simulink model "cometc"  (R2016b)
settings: Solver=ode45  StartTime=0.0  StopTime=298.0  RelTol=1e-3  EnableMultiTasking=on
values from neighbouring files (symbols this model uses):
  d11 = 215*100    (= 21500)    [parameter.m]
  d22 = 147*10^3    (= 147000)    [parameter.m]
  d33 = 802*10^4    (= 8020000)    [parameter.m]
  delta1 = 0.00001    (= 1e-05)    [parameter.m]
  delta2 = 0.0001    [parameter.m]
  garma1 = 10000    [parameter.m]
  garma2 = 100    [parameter.m]
  kr = 0.05    [parameter.m]
  krou = 0.4    [parameter.m]
  ktheat = 0.8    [parameter.m]
  ku = 0.05    [parameter.m]
  lam0 = 0    [parameter.m]
  m11 = 120*10^3    (= 120000)    [parameter.m]
  m22 = 177.9*10^3    (= 177900)    [parameter.m]
  m33 = 636*10^5    (= 63600000)    [parameter.m]
  rou0 = 10    [parameter.m]
  T1 = 0.8    [parameter.m]
  T2 = 0.3    [parameter.m]
libraries: simulink x4

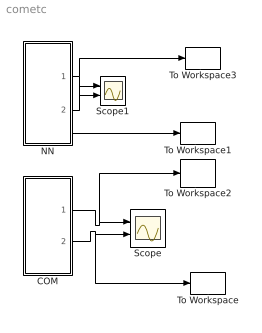
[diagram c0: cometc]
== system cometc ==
  COM : Subsystem
  NN : Subsystem
  Scope : Scope  NumInputPorts=2
  Scope1 : Scope  NumInputPorts=2
  To Workspace : ToWorkspace  VariableName=comtheat  SampleTime=-1
  To Workspace1 : ToWorkspace  VariableName=nntheat  SampleTime=-1
  To Workspace2 : ToWorkspace  VariableName=comrou  SampleTime=-1
  To Workspace3 : ToWorkspace  VariableName=nnrou  SampleTime=-1
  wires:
  NN/1(rous) -> To Workspace3/1, Scope1/1
  NN/2(theta) -> To Workspace1/1, Scope1/2
  COM/1(rous) -> To Workspace2/1, Scope/1
  COM/2(theta) -> To Workspace/1, Scope/2

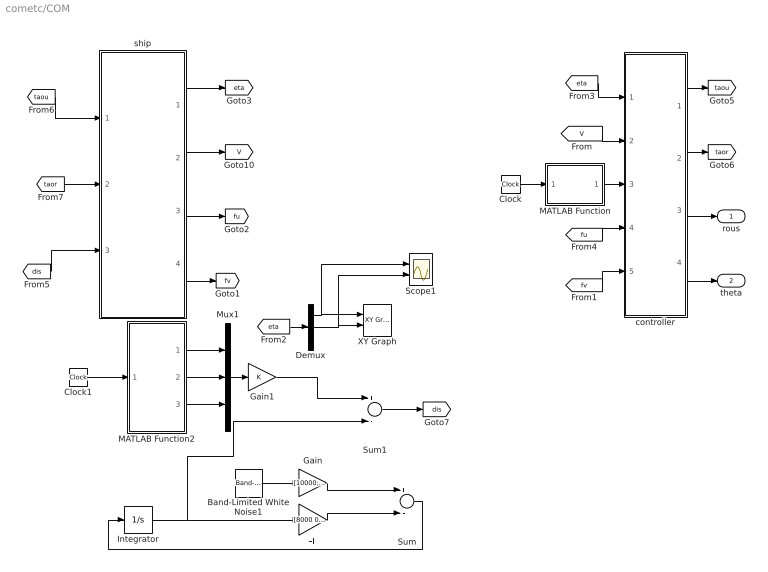
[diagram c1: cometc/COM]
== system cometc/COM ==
  -T : Gain  Gain=[8000 0 0;0 8000 0;0 0 80000]  Multiplication=Matrix(K*u)
  Band-Limited White Noise1 : simulink/Sources/Band-Limited White Noise  Cov=[0.1]  Ts=0.1  seed=[23341]
  Clock : Clock
  Clock1 : Clock
  Demux : Demux  Outputs=3
  Gain : Gain  Gain=[10000;10000;100000]
  Gain1 : Gain
  Integrator : Integrator  InitialCondition=[0;0;0]
  MATLAB Function : MATLAB Function  TreatAsAtomicUnit=on
  MATLAB Function2 : MATLAB Function  TreatAsAtomicUnit=on
  Mux1 : Mux  Inputs=3
  Scope1 : Scope  NumInputPorts=2
  Sum : Sum  Inputs=+-
  Sum1 : Sum  Inputs=+-
  XY Graph : simulink/Sinks/XY Graph  xmin=-240  xmax=240  ymin=-240  ymax=240  st=0.02
  controller : Subsystem
  ship : Subsystem
  rous : Outport
  theta : Outport  Port=2
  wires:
  [eta] -> controller/1(eta)
  ship/3(fu) -> [fu]
  MATLAB Function2/1(xd) -> Mux1/1
  MATLAB Function2/2(yd) -> Mux1/2
  MATLAB Function2/3(zd) -> Mux1/3
  [eta] -> Demux/1
  Mux1/1 -> Gain1/1
  [fv] -> controller/5(fr)
  ship/4(fv) -> [fv]
  Clock1/1 -> MATLAB Function2/1(t)
  [fu] -> controller/4(fu)
  ship/2(V) -> [V]
  ship/1(eta) -> [eta]
  [V] -> controller/2(V)
  controller/2(t_rc) -> [taor]
  controller/1(t_uc) -> [taou]
  [taor] -> ship/2(tao_r)
  [taou] -> ship/1(tao_u)
  Clock/1 -> MATLAB Function/1(t)
  [dis] -> ship/3(tao_w)
  MATLAB Function/1(xdyd) -> controller/3(xdyd)
  Demux/2 -> Scope1/2, XY Graph/2
  Demux/1 -> Scope1/1, XY Graph/1
  controller/3(rous) -> rous/1
  controller/4(theta) -> theta/1
  Gain/1 -> Sum/1
  Sum/1 -> Integrator/1
  Integrator/1 -> Sum1/2, -T/1
  -T/1 -> Sum/2
  Band-Limited White Noise1/1 -> Gain/1
  Sum1/1 -> [dis]
  Gain1/1 -> Sum1/1

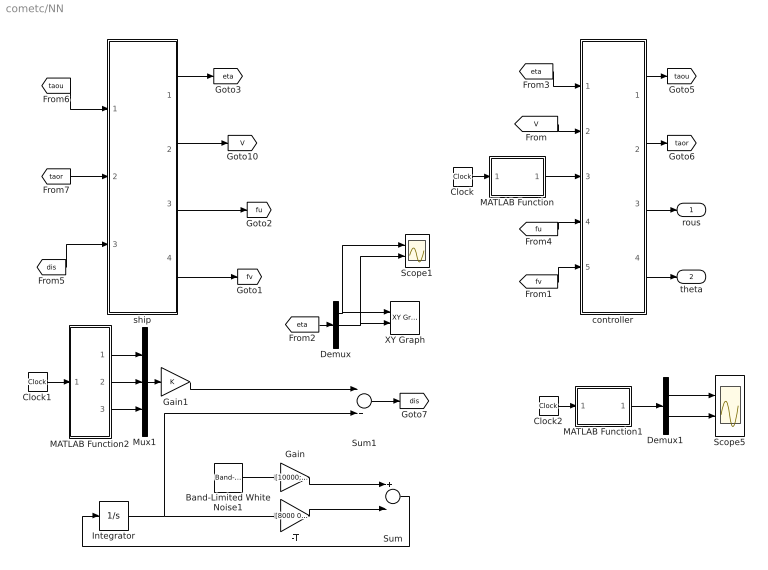
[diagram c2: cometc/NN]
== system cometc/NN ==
  -T : Gain  Gain=[8000 0 0;0 8000 0;0 0 80000]  Multiplication=Matrix(K*u)
  Band-Limited White Noise1 : simulink/Sources/Band-Limited White Noise  Cov=[0.1]  Ts=0.1  seed=[23341]
  Clock : Clock
  Clock1 : Clock
  Clock2 : Clock
  Demux : Demux  Outputs=3
  Demux1 : Demux  Outputs=2
  Gain : Gain  Gain=[10000;10000;100000]
  Gain1 : Gain
  Integrator : Integrator  InitialCondition=[0;0;0]
  MATLAB Function : MATLAB Function  TreatAsAtomicUnit=on
  MATLAB Function1 : MATLAB Function  TreatAsAtomicUnit=on
  MATLAB Function2 : MATLAB Function  TreatAsAtomicUnit=on
  Mux1 : Mux  Inputs=3
  Scope1 : Scope  NumInputPorts=2
  Scope5 : Scope  NumInputPorts=2
  Sum : Sum  Inputs=+-
  Sum1 : Sum
  XY Graph : simulink/Sinks/XY Graph  xmin=-240  xmax=240  ymin=-240  ymax=240  st=0.02
  controller : Subsystem
  ship : Subsystem
  rous : Outport
  theta : Outport  Port=2
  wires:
  MATLAB Function/1(xdyd) -> controller/3(xdyd)
  [dis] -> ship/3(tao_w)
  Clock/1 -> MATLAB Function/1(t)
  Demux/2 -> Scope1/2, XY Graph/2
  [taou] -> ship/1(tao_u)
  [taor] -> ship/2(tao_r)
  controller/1(t_uc) -> [taou]
  controller/2(t_rc) -> [taor]
  [V] -> controller/2(V)
  ship/1(eta) -> [eta]
  ship/2(V) -> [V]
  [fu] -> controller/4(fu)
  Clock1/1 -> MATLAB Function2/1(t)
  ship/4(fv) -> [fv]
  [fv] -> controller/5(fr)
  Mux1/1 -> Gain1/1
  [eta] -> Demux/1
  MATLAB Function2/3(zd) -> Mux1/3
  MATLAB Function2/2(yd) -> Mux1/2
  MATLAB Function2/1(xd) -> Mux1/1
  ship/3(fu) -> [fu]
  [eta] -> controller/1(eta)
  Clock2/1 -> MATLAB Function1/1(t)
  MATLAB Function1/1(xdyd) -> Demux1/1
  Demux1/1 -> Scope5/1
  Demux1/2 -> Scope5/2
  Demux/1 -> Scope1/1, XY Graph/1
  controller/3(rous) -> rous/1
  controller/4(theta) -> theta/1
  Gain/1 -> Sum/1
  Sum/1 -> Integrator/1
  Integrator/1 -> Sum1/2, -T/1
  -T/1 -> Sum/2
  Band-Limited White Noise1/1 -> Gain/1
  Sum1/1 -> [dis]
  Gain1/1 -> Sum1/1

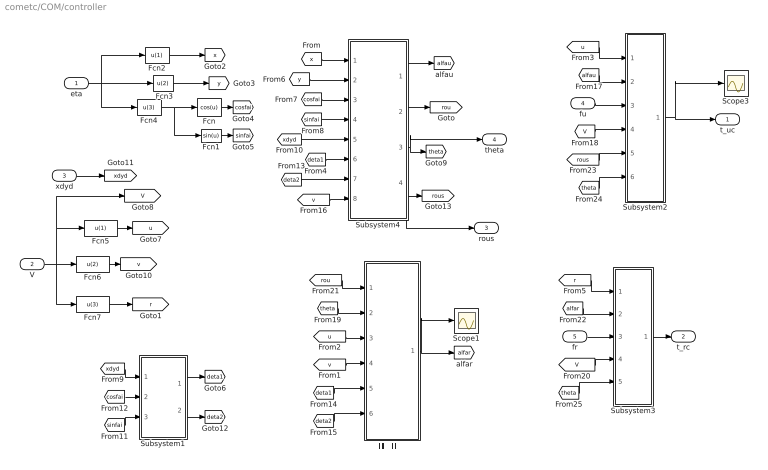
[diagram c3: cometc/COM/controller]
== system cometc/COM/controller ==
  eta : Inport
  V : Inport  Port=2
  xdyd : Inport  Port=3
  fu : Inport  Port=4
  fr : Inport  Port=5
  Fcn : Fcn  Expr=cos(u)
  Fcn1 : Fcn  Expr=sin(u)
  Fcn2 : Fcn  Expr=u(1)
  Fcn3 : Fcn  Expr=u(2)
  Fcn4 : Fcn  Expr=u(3)
  Fcn5 : Fcn  Expr=u(1)
  Fcn6 : Fcn  Expr=u(2)
  Fcn7 : Fcn  Expr=u(3)
  Scope1 : Scope
  Scope3 : Scope
  Subsystem1 : Subsystem
  Subsystem2 : Subsystem
  Subsystem3 : Subsystem
  Subsystem4 : Subsystem
  转向虚拟控制 : Subsystem
  t_uc : Outport
  t_rc : Outport  Port=2
  rous : Outport  Port=3
  theta : Outport  Port=4
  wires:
  [theta] -> Subsystem3/5(theta)
  [theta] -> Subsystem2/6(theta)
  [rous] -> Subsystem2/5(rous)
  [V] -> Subsystem3/4(V)
  [V] -> Subsystem2/4(V)
  fu/1 -> Subsystem2/3(fu)
  Subsystem4/2(rou) -> [rou]
  [v] -> Subsystem4/8(v)
  [deta2] -> Subsystem4/7(deta2)
  [deta1] -> Subsystem4/6(deta1)
  Subsystem4/1(alfau) -> [alfau]
  [xdyd] -> Subsystem4/5(xdyd)
  [sinfai] -> Subsystem4/4(sinfai)
  [cosfai] -> Subsystem4/3(cosfai)
  [y] -> Subsystem4/2(y)
  [x] -> Subsystem4/1(x)
  [alfar] -> Subsystem3/2(ar)
  [rou] -> 转向虚拟控制/1(rou)
  [theta] -> 转向虚拟控制/2(theta)
  [alfau] -> Subsystem2/2(au)
  [deta2] -> 转向虚拟控制/6(deta2)
  [deta1] -> 转向虚拟控制/5(deta1)
  Subsystem1/1(deta1) -> [deta1]
  Subsystem1/2(deta2) -> [deta2]
  [cosfai] -> Subsystem1/2(cosp)
  [sinfai] -> Subsystem1/3(sinp)
  [xdyd] -> Subsystem1/1(xdyd)
  xdyd/1 -> [xdyd]
  Fcn2/1 -> [x]
  Fcn1/1 -> [sinfai]
  Fcn/1 -> [cosfai]
  Fcn3/1 -> [y]
  Subsystem2/1(t_u) -> t_uc/1, Scope3/1
  Subsystem3/1(t_r) -> t_rc/1
  转向虚拟控制/1(ar) -> Scope1/1, [alfar]
  [v] -> 转向虚拟控制/4(v)
  Fcn7/1 -> [r]
  fr/1 -> Subsystem3/3(fr)
  [u] -> 转向虚拟控制/3(u)
  Fcn5/1 -> [u]
  V/1 -> Fcn5/1, [V], Fcn6/1, Fcn7/1
  Fcn6/1 -> [v]
  Fcn4/1 -> Fcn/1, Fcn1/1
  eta/1 -> Fcn4/1, Fcn2/1, Fcn3/1
  [u] -> Subsystem2/1(u)
  [r] -> Subsystem3/1(r)
  Subsystem4/4(rous) -> rous/1, [rous]
  Subsystem4/3(theta) -> theta/1, [theta]

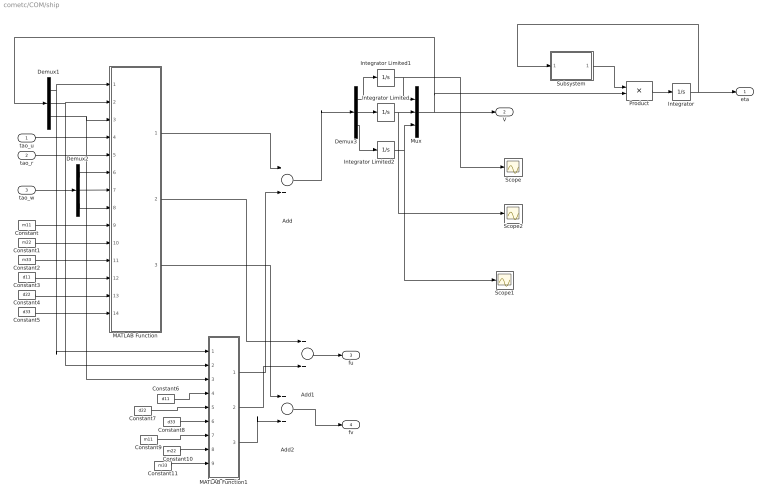
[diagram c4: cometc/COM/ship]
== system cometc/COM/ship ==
  tao_u : Inport
  tao_r : Inport  Port=2
  tao_w : Inport  Port=3
  Add : Sum
  Add1 : Sum
  Add2 : Sum
  Constant : Constant  Value=m11
  Constant1 : Constant  Value=m22
  Constant10 : Constant  Value=m22
  Constant11 : Constant  Value=m33
  Constant2 : Constant  Value=m33
  Constant3 : Constant  Value=d11
  Constant4 : Constant  Value=d22
  Constant5 : Constant  Value=d33
  Constant6 : Constant  Value=d11
  Constant7 : Constant  Value=d22
  Constant8 : Constant  Value=d33
  Constant9 : Constant  Value=m11
  Demux1 : Demux  Outputs=3
  Demux2 : Demux  Outputs=3
  Demux3 : Demux  Outputs=3
  Integrator : Integrator  InitialCondition=[20;190;-0.02*pi]
  Integrator Limited : Integrator  UpperSaturationLimit=15  LowerSaturationLimit=-15
  Integrator Limited1 : Integrator  UpperSaturationLimit=3  LowerSaturationLimit=-3
  Integrator Limited2 : Integrator  UpperSaturationLimit=1  LowerSaturationLimit=-1
  MATLAB Function : MATLAB Function  TreatAsAtomicUnit=on
  MATLAB Function1 : MATLAB Function  TreatAsAtomicUnit=on
  Mux : Mux  Inputs=3
  Product : Product  Multiplication=Matrix(*)
  Scope : Scope
  Scope1 : Scope
  Scope2 : Scope
  Subsystem : Subsystem
  eta : Outport
  V : Outport  Port=2
  fu : Outport  Port=3
  fv : Outport  Port=4
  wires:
  Integrator Limited/1 -> Scope2/1, Mux/2
  Integrator/1 -> Subsystem/1(In1), eta/1
  MATLAB Function/2(fu) -> Add1/1
  Mux/1 -> V/1, Demux1/1, Product/2
  Integrator Limited2/1 -> Mux/3, Scope1/1
  Integrator Limited1/1 -> Mux/1, Scope/1
  Demux3/3 -> Integrator Limited2/1
  Demux3/1 -> Integrator Limited1/1
  MATLAB Function/1(dot) -> Add/1
  Demux3/2 -> Integrator Limited/1
  tao_w/1 -> Demux2/1
  Constant5/1 -> MATLAB Function/14(d33)
  Constant4/1 -> MATLAB Function/13(d22)
  Constant3/1 -> MATLAB Function/12(d11)
  Constant2/1 -> MATLAB Function/11(m33)
  Constant1/1 -> MATLAB Function/10(m22)
  Constant/1 -> MATLAB Function/9(m11)
  Demux2/3 -> MATLAB Function/8(tao_wr)
  Demux2/2 -> MATLAB Function/7(tao_wv)
  Demux2/1 -> MATLAB Function/6(tao_wu)
  tao_u/1 -> MATLAB Function/4(tao_u)
  tao_r/1 -> MATLAB Function/5(tao_r)
  Demux1/3 -> MATLAB Function1/3(r), MATLAB Function/3(r)
  Demux1/2 -> MATLAB Function/2(v), MATLAB Function1/2(v)
  Demux1/1 -> MATLAB Function1/1(u), MATLAB Function/1(u)
  Subsystem/1(Out1) -> Product/1
  Product/1 -> Integrator/1
  Constant7/1 -> MATLAB Function1/5(d22)
  Constant6/1 -> MATLAB Function1/4(d11)
  Constant8/1 -> MATLAB Function1/6(d33)
  MATLAB Function1/1(dot) -> Add/2
  MATLAB Function1/2(fu) -> Add1/2
  Add1/1 -> fu/1
  MATLAB Function1/3(fr) -> Add2/2
  MATLAB Function/3(fr) -> Add2/1
  Add2/1 -> fv/1
  Add/1 -> Demux3/1
  Constant9/1 -> MATLAB Function1/7(m11)
  Constant10/1 -> MATLAB Function1/8(m22)
  Constant11/1 -> MATLAB Function1/9(m33)

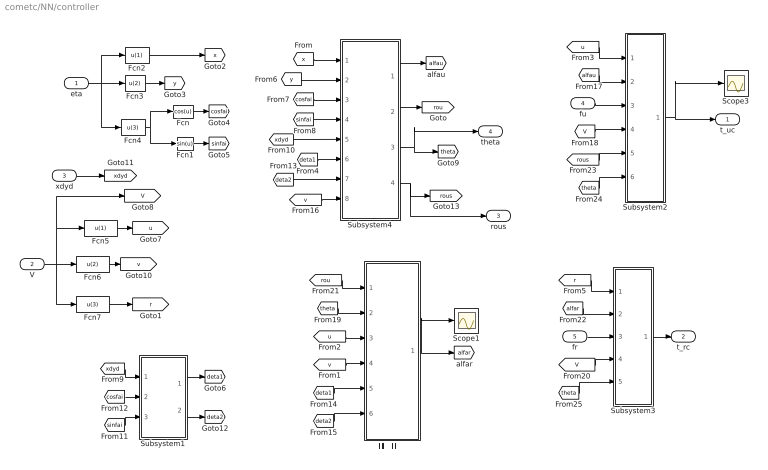
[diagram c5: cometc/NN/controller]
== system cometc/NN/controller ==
  eta : Inport
  V : Inport  Port=2
  xdyd : Inport  Port=3
  fu : Inport  Port=4
  fr : Inport  Port=5
  Fcn : Fcn  Expr=cos(u)
  Fcn1 : Fcn  Expr=sin(u)
  Fcn2 : Fcn  Expr=u(1)
  Fcn3 : Fcn  Expr=u(2)
  Fcn4 : Fcn  Expr=u(3)
  Fcn5 : Fcn  Expr=u(1)
  Fcn6 : Fcn  Expr=u(2)
  Fcn7 : Fcn  Expr=u(3)
  Scope1 : Scope
  Scope3 : Scope
  Subsystem1 : Subsystem
  Subsystem2 : Subsystem
  Subsystem3 : Subsystem
  Subsystem4 : Subsystem
  转向虚拟控制 : Subsystem
  t_uc : Outport
  t_rc : Outport  Port=2
  rous : Outport  Port=3
  theta : Outport  Port=4
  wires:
  [r] -> Subsystem3/1(r)
  [u] -> Subsystem2/1(u)
  eta/1 -> Fcn3/1, Fcn2/1, Fcn4/1
  Fcn4/1 -> Fcn/1, Fcn1/1
  Fcn6/1 -> [v]
  V/1 -> Fcn7/1, Fcn6/1, [V], Fcn5/1
  Fcn5/1 -> [u]
  [u] -> 转向虚拟控制/3(u)
  fr/1 -> Subsystem3/3(fr)
  Fcn7/1 -> [r]
  [v] -> 转向虚拟控制/4(v)
  转向虚拟控制/1(ar) -> [alfar], Scope1/1
  Subsystem3/1(t_r) -> t_rc/1
  Subsystem2/1(t_u) -> Scope3/1, t_uc/1
  Fcn3/1 -> [y]
  Fcn/1 -> [cosfai]
  Fcn1/1 -> [sinfai]
  Fcn2/1 -> [x]
  xdyd/1 -> [xdyd]
  [xdyd] -> Subsystem1/1(xdyd)
  [sinfai] -> Subsystem1/3(sinp)
  [cosfai] -> Subsystem1/2(cosp)
  Subsystem1/2(deta2) -> [deta2]
  Subsystem1/1(deta1) -> [deta1]
  [deta1] -> 转向虚拟控制/5(deta1)
  [deta2] -> 转向虚拟控制/6(deta2)
  [alfau] -> Subsystem2/2(au)
  [theta] -> 转向虚拟控制/2(theta)
  [rou] -> 转向虚拟控制/1(rou)
  [alfar] -> Subsystem3/2(ar)
  [x] -> Subsystem4/1(x)
  [y] -> Subsystem4/2(y)
  [cosfai] -> Subsystem4/3(cosfai)
  [sinfai] -> Subsystem4/4(sinfai)
  [xdyd] -> Subsystem4/5(xdyd)
  Subsystem4/1(alfau) -> [alfau]
  [deta1] -> Subsystem4/6(deta1)
  [deta2] -> Subsystem4/7(deta2)
  [v] -> Subsystem4/8(v)
  Subsystem4/2(rou) -> [rou]
  fu/1 -> Subsystem2/3(fu)
  [V] -> Subsystem2/4(V)
  Subsystem4/4(rous) -> rous/1, [rous]
  [V] -> Subsystem3/4(V)
  [rous] -> Subsystem2/5(rous)
  [theta] -> Subsystem2/6(theta)
  [theta] -> Subsystem3/5(theta)
  Subsystem4/3(theta) -> theta/1, [theta]

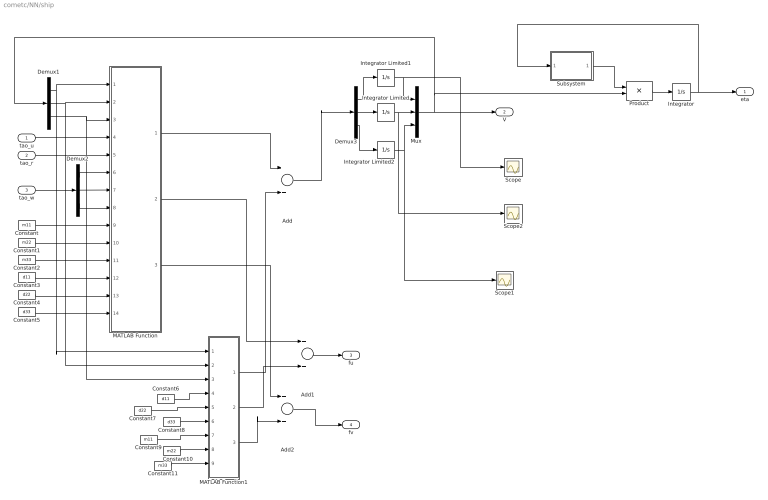
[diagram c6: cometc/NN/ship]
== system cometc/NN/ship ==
  tao_u : Inport
  tao_r : Inport  Port=2
  tao_w : Inport  Port=3
  Add : Sum
  Add1 : Sum
  Add2 : Sum
  Constant : Constant  Value=m11
  Constant1 : Constant  Value=m22
  Constant10 : Constant  Value=m22
  Constant11 : Constant  Value=m33
  Constant2 : Constant  Value=m33
  Constant3 : Constant  Value=d11
  Constant4 : Constant  Value=d22
  Constant5 : Constant  Value=d33
  Constant6 : Constant  Value=d11
  Constant7 : Constant  Value=d22
  Constant8 : Constant  Value=d33
  Constant9 : Constant  Value=m11
  Demux1 : Demux  Outputs=3
  Demux2 : Demux  Outputs=3
  Demux3 : Demux  Outputs=3
  Integrator : Integrator  InitialCondition=[20;190;-0.02*pi]
  Integrator Limited : Integrator  UpperSaturationLimit=15  LowerSaturationLimit=-15
  Integrator Limited1 : Integrator  UpperSaturationLimit=3  LowerSaturationLimit=-3
  Integrator Limited2 : Integrator  UpperSaturationLimit=1  LowerSaturationLimit=-1
  MATLAB Function : MATLAB Function  TreatAsAtomicUnit=on
  MATLAB Function1 : MATLAB Function  TreatAsAtomicUnit=on
  Mux : Mux  Inputs=3
  Product : Product  Multiplication=Matrix(*)
  Scope : Scope
  Scope1 : Scope
  Scope2 : Scope
  Subsystem : Subsystem
  eta : Outport
  V : Outport  Port=2
  fu : Outport  Port=3
  fv : Outport  Port=4
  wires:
  Integrator Limited/1 -> Scope2/1, Mux/2
  Integrator/1 -> Subsystem/1(In1), eta/1
  MATLAB Function/2(fu) -> Add1/1
  Mux/1 -> V/1, Demux1/1, Product/2
  Integrator Limited2/1 -> Mux/3, Scope1/1
  Integrator Limited1/1 -> Mux/1, Scope/1
  Demux3/3 -> Integrator Limited2/1
  Demux3/1 -> Integrator Limited1/1
  MATLAB Function/1(dot) -> Add/1
  Demux3/2 -> Integrator Limited/1
  tao_w/1 -> Demux2/1
  Constant5/1 -> MATLAB Function/14(d33)
  Constant4/1 -> MATLAB Function/13(d22)
  Constant3/1 -> MATLAB Function/12(d11)
  Constant2/1 -> MATLAB Function/11(m33)
  Constant1/1 -> MATLAB Function/10(m22)
  Constant/1 -> MATLAB Function/9(m11)
  Demux2/3 -> MATLAB Function/8(tao_wr)
  Demux2/2 -> MATLAB Function/7(tao_wv)
  Demux2/1 -> MATLAB Function/6(tao_wu)
  tao_u/1 -> MATLAB Function/4(tao_u)
  tao_r/1 -> MATLAB Function/5(tao_r)
  Demux1/3 -> MATLAB Function1/3(r), MATLAB Function/3(r)
  Demux1/2 -> MATLAB Function/2(v), MATLAB Function1/2(v)
  Demux1/1 -> MATLAB Function1/1(u), MATLAB Function/1(u)
  Subsystem/1(Out1) -> Product/1
  Product/1 -> Integrator/1
  Constant7/1 -> MATLAB Function1/5(d22)
  Constant6/1 -> MATLAB Function1/4(d11)
  Constant8/1 -> MATLAB Function1/6(d33)
  MATLAB Function1/1(dot) -> Add/2
  MATLAB Function1/2(fu) -> Add1/2
  Add1/1 -> fu/1
  MATLAB Function1/3(fr) -> Add2/2
  MATLAB Function/3(fr) -> Add2/1
  Add2/1 -> fv/1
  Add/1 -> Demux3/1
  Constant9/1 -> MATLAB Function1/7(m11)
  Constant10/1 -> MATLAB Function1/8(m22)
  Constant11/1 -> MATLAB Function1/9(m33)

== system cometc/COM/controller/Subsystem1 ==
  xdyd : Inport
  cosp : Inport  Port=2
  sinp : Inport  Port=3
  Add : Sum  Inputs=--
  Add1 : Sum  Inputs=+-
  Derivative : Derivative
  Derivative2 : Derivative
  Product{5,7..9} (4 alike) : Product
  Selector1 : Selector  InputPortWidth=2  IndexOptions=Index vector (dialog)  Indices=[2]  OutputSizes=1
  Selector4 : Selector  InputPortWidth=2  IndexOptions=Index vector (dialog)  Indices=[1]  OutputSizes=1
  deta1 : Outport
  deta2 : Outport  Port=2
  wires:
  Add1/1 -> deta2/1
  Add/1 -> deta1/1
  Product8/1 -> Add1/2
  Product7/1 -> Add1/1
  Product9/1 -> Add/2
  Product5/1 -> Add/1
  cosp/1 -> Product5/2, Product8/1
  sinp/1 -> Product9/1, Product7/2
  xdyd/1 -> Selector4/1, Selector1/1
  Selector1/1 -> Derivative2/1
  Selector4/1 -> Derivative/1
  Derivative/1 -> Product7/1, Product5/1
  Derivative2/1 -> Product9/2, Product8/2

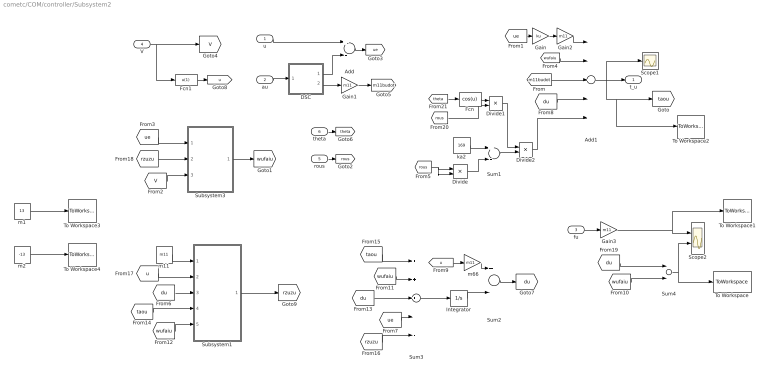
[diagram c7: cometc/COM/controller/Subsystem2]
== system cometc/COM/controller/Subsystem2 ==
  u : Inport
  au : Inport  Port=2
  fu : Inport  Port=3
  V : Inport  Port=4
  rous : Inport  Port=5
  theta : Inport  Port=6
  " m66" : Gain  Gain=m11
  Add : Sum  Inputs=+-
  Add1 : Sum  Inputs=--+-+
  DSC : Subsystem
  Divide : Product  Inputs=**
  Divide1 : Product  Inputs=**
  Divide2 : Product  Inputs=*/
  Fcn : Fcn  Expr=cos(u)
  Fcn1 : Fcn  Expr=u(1)
  Gain : Gain  Gain=ku
  Gain1 : Gain  Gain=m11
  Gain2 : Gain  Gain=m11
  Gain3 : Gain  Gain=m11
  Integrator : Integrator
  Scope1 : Scope
  Scope2 : Scope  NumInputPorts=2
  Subsystem1 : Subsystem
  Subsystem3 : Subsystem
  Sum1 : Sum  Inputs=+-
  Sum2 : Sum  Inputs=+-
  Sum3 : Sum  Inputs=+++--
  Sum4 : Sum
  To Workspace : ToWorkspace  VariableName=uncertainucom  SampleTime=-1
  To Workspace1 : ToWorkspace  VariableName=uncertainuu  SampleTime=-1
  To Workspace2 : ToWorkspace  VariableName=comtaou  SampleTime=-1
  To Workspace3 : ToWorkspace  VariableName=uplim  SampleTime=-1
  To Workspace4 : ToWorkspace  VariableName=xialim  SampleTime=-1
  ka2 : Constant  Value=169
  m1 : Constant  Value=13
  m11 : Constant  Value=m11
  m2 : Constant  Value=-13
  t_u : Outport
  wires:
  Divide2/1 -> Add1/5
  Sum1/1 -> Divide2/2
  Divide1/1 -> Divide2/1
  [rous] -> Divide1/2
  Fcn/1 -> Divide1/1
  [theta] -> Fcn/1
  theta/1 -> [theta]
  Divide/1 -> Sum1/2
  [rous] -> Divide/1, Divide/2
  rous/1 -> [rous]
  ka2/1 -> Sum1/1
  [taou] -> Sum3/1
  [wufaiu] -> Sum4/2
  [du] -> Sum4/1
  [du] -> Add1/4
  [rzuzu] -> Subsystem3/2(rzuzu)
  Fcn1/1 -> [u]
  V/1 -> [V], Fcn1/1
  [u] -> " m66"/1
  [rzuzu] -> Sum3/5
  Sum2/1 -> [du]
  [wufaiu] -> Sum3/2
  [du] -> Sum3/3
  [ue] -> Sum3/4
  " m66"/1 -> Sum2/1
  Integrator/1 -> Sum2/2
  Sum3/1 -> Integrator/1
  Subsystem1/1(γzrZr) -> [rzuzu]
  [u] -> Subsystem1/2(u)
  [taou] -> Subsystem1/4(tao-u)
  [wufaiu] -> Subsystem1/5(W ̂u^T φu)
  [du] -> Subsystem1/3((D_u) ̂)
  m11/1 -> Subsystem1/1(m11)
  [wufaiu] -> Add1/2
  [ue] -> Subsystem3/1(ue)
  [V] -> Subsystem3/3(u)
  Subsystem3/1(W ̂u^T φu) -> [wufaiu]
  Gain1/1 -> [m11budot]
  DSC/2(d_bu) -> Gain1/1
  [ue] -> Gain/1
  Add/1 -> [ue]
  [m11budot] -> Add1/3
  Gain2/1 -> Add1/1
  DSC/1(b_u) -> Add/2
  fu/1 -> Gain3/1
  Gain/1 -> Gain2/1
  u/1 -> Add/1
  au/1 -> DSC/1(au)
  Gain3/1 -> To Workspace1/1, Scope2/1
  Sum4/1 -> Scope2/2, To Workspace/1
  Add1/1 -> To Workspace2/1, [taou], t_u/1, Scope1/1
  m1/1 -> To Workspace3/1
  m2/1 -> To Workspace4/1

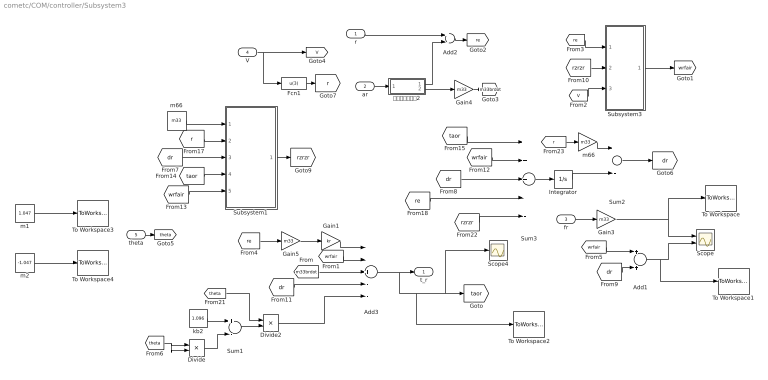
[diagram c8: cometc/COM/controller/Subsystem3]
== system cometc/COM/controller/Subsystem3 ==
  r : Inport
  ar : Inport  Port=2
  fr : Inport  Port=3
  V : Inport  Port=4
  theta : Inport  Port=5
  " m66" : Gain  Gain=m33
  Add1 : Sum
  Add2 : Sum  Inputs=+-
  Add3 : Sum  Inputs=--+--
  Divide : Product  Inputs=**
  Divide2 : Product  Inputs=*/
  Fcn1 : Fcn  Expr=u(3)
  Gain1 : Gain  Gain=kr
  Gain3 : Gain  Gain=m33
  Gain4 : Gain  Gain=m33
  Gain5 : Gain  Gain=m33
  Integrator : Integrator
  Scope : Scope  NumInputPorts=2
  Scope4 : Scope
  Subsystem1 : Subsystem
  Subsystem3 : Subsystem
  Sum1 : Sum  Inputs=+-
  Sum2 : Sum  Inputs=+-
  Sum3 : Sum  Inputs=+++--
  To Workspace : ToWorkspace  VariableName=uncertainrr  SampleTime=-1
  To Workspace1 : ToWorkspace  VariableName=uncertainrcom  SampleTime=-1
  To Workspace2 : ToWorkspace  VariableName=comtaor  SampleTime=-1
  To Workspace3 : ToWorkspace  VariableName=uplim1  SampleTime=-1
  To Workspace4 : ToWorkspace  VariableName=xialim1  SampleTime=-1
  kb2 : Constant  Value=1.096
  m1 : Constant  Value=1.047
  m2 : Constant  Value=-1.047
  m66 : Constant  Value=m33
  一阶低通滤波器2 : Subsystem
  t_r : Outport
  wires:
  theta/1 -> [theta]
  Divide2/1 -> Add3/5
  Sum1/1 -> Divide2/2
  [theta] -> Divide2/1
  Divide/1 -> Sum1/2
  [theta] -> Divide/1, Divide/2
  kb2/1 -> Sum1/1
  [dr] -> Add3/4
  [dr] -> Add1/2
  Fcn1/1 -> [r]
  [rzrzr] -> Subsystem3/2(rzuzu)
  [r] -> " m66"/1
  [rzrzr] -> Sum3/5
  Sum2/1 -> [dr]
  [taor] -> Sum3/1
  [wrfair] -> Sum3/2
  [dr] -> Sum3/3
  [re] -> Sum3/4
  " m66"/1 -> Sum2/1
  Integrator/1 -> Sum2/2
  Sum3/1 -> Integrator/1
  Subsystem1/1(γzrZr) -> [rzrzr]
  [r] -> Subsystem1/2(r)
  [taor] -> Subsystem1/4(tao-r)
  [wrfair] -> Subsystem1/5(W ̂r^T φr)
  [dr] -> Subsystem1/3((D_r ) ̂)
  m66/1 -> Subsystem1/1(m33)
  [wrfair] -> Add1/1
  [re] -> Gain5/1
  [wrfair] -> Add3/2
  [m33brdot] -> Add3/3
  Gain4/1 -> [m33brdot]
  V/1 -> [V], Fcn1/1
  [re] -> Subsystem3/1(ue)
  [V] -> Subsystem3/3(u)
  Subsystem3/1(W ̂u^T φu) -> [wrfair]
  Gain5/1 -> Gain1/1
  一阶低通滤波器2/2(d_ar) -> Gain4/1
  一阶低通滤波器2/1(ar1) -> Add2/2
  fr/1 -> Gain3/1
  Gain1/1 -> Add3/1
  Add2/1 -> [re]
  r/1 -> Add2/1
  ar/1 -> 一阶低通滤波器2/1(ar)
  Gain3/1 -> Scope/1, To Workspace/1
  Add1/1 -> To Workspace1/1, Scope/2
  Add3/1 -> t_r/1, To Workspace2/1, [taor], Scope4/1
  m1/1 -> To Workspace3/1
  m2/1 -> To Workspace4/1

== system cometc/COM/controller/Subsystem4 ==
  x : Inport
  y : Inport  Port=2
  cosfai : Inport  Port=3
  sinfai : Inport  Port=4
  xdyd : Inport  Port=5
  deta1 : Inport  Port=6
  deta2 : Inport  Port=7
  v : Inport  Port=8
  Scope1 : Scope
  Scope2 : Scope
  Scope3 : Scope
  Subsystem : Subsystem
  纵向虚拟控制 : Subsystem
  alfau : Outport
  rou : Outport  Port=2
  theta : Outport  Port=3
  rous : Outport  Port=4
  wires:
  纵向虚拟控制/2(rous) -> rous/1, Scope1/1
  [rou] -> 纵向虚拟控制/1(rou)
  Subsystem/2(theta) -> [theta], theta/1, Scope3/1
  [theta] -> 纵向虚拟控制/2(theta)
  y/1 -> Subsystem/2(y)
  xdyd/1 -> Subsystem/5(xdyd)
  x/1 -> Subsystem/1(x)
  sinfai/1 -> Subsystem/4(sinp)
  deta1/1 -> 纵向虚拟控制/4(deta1)
  纵向虚拟控制/1(au) -> alfau/1, Scope2/1
  cosfai/1 -> Subsystem/3(cosp)
  deta2/1 -> 纵向虚拟控制/5(deta2)
  v/1 -> 纵向虚拟控制/3(v)
  Subsystem/1(rou) -> [rou], rou/1

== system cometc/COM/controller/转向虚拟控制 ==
  rou : Inport
  theta : Inport  Port=2
  u : Inport  Port=3
  v : Inport  Port=4
  deta1 : Inport  Port=5
  deta2 : Inport  Port=6
  Add : Sum
  Add1 : Sum  Inputs=--++
  Add2 : Sum  Inputs=+-
  Constant : Constant  Value=lam0
  Divide : Product  Inputs=*/
  Fcn2 : Fcn  Expr=sin(u)
  Fcn3 : Fcn  Expr=cos(u)
  Gain : Gain  Gain=ktheat
  Product{,1..3} (4 alike) : Product
  ar : Outport
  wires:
  Constant/1 -> Add2/2
  Add2/1 -> Gain/1
  Add/1 -> ar/1
  Gain/1 -> Add/2
  Divide/1 -> Add/1
  Fcn3/1 -> Product2/1, Product/1
  Fcn2/1 -> Product1/1, Product3/1
  deta2/1 -> Product/2
  v/1 -> Product2/2
  deta1/1 -> Product3/2
  u/1 -> Product1/2
  Product2/1 -> Add1/3
  Product3/1 -> Add1/2
  Product1/1 -> Add1/1
  Product/1 -> Add1/4
  rou/1 -> Divide/2
  Add1/1 -> Divide/1
  theta/1 -> Fcn3/1, Add2/1, Fcn2/1

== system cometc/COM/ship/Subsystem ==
  In1 : Inport
  MATLAB Function1 : MATLAB Function  TreatAsAtomicUnit=on
  Selector3 : Selector  InputPortWidth=3  IndexOptions=Index vector (dialog)  Indices=[3]  OutputSizes=1
  Out1 : Outport
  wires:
  Selector3/1 -> MATLAB Function1/1(psi)
  In1/1 -> Selector3/1
  MATLAB Function1/1(y) -> Out1/1

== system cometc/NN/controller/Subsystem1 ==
  xdyd : Inport
  cosp : Inport  Port=2
  sinp : Inport  Port=3
  Add : Sum  Inputs=--
  Add1 : Sum  Inputs=+-
  Derivative : Derivative
  Derivative2 : Derivative
  Product{5,7..9} (4 alike) : Product
  Selector1 : Selector  InputPortWidth=2  IndexOptions=Index vector (dialog)  Indices=[2]  OutputSizes=1
  Selector4 : Selector  InputPortWidth=2  IndexOptions=Index vector (dialog)  Indices=[1]  OutputSizes=1
  deta1 : Outport
  deta2 : Outport  Port=2
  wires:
  Derivative2/1 -> Product8/2, Product9/2
  Derivative/1 -> Product5/1, Product7/1
  Selector4/1 -> Derivative/1
  Selector1/1 -> Derivative2/1
  xdyd/1 -> Selector1/1, Selector4/1
  sinp/1 -> Product7/2, Product9/1
  cosp/1 -> Product8/1, Product5/2
  Product5/1 -> Add/1
  Product9/1 -> Add/2
  Product7/1 -> Add1/1
  Product8/1 -> Add1/2
  Add/1 -> deta1/1
  Add1/1 -> deta2/1

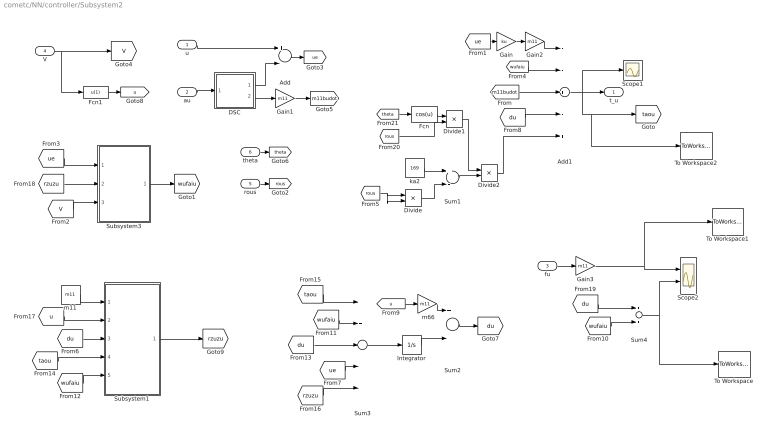
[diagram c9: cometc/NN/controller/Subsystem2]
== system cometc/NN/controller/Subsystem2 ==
  u : Inport
  au : Inport  Port=2
  fu : Inport  Port=3
  V : Inport  Port=4
  rous : Inport  Port=5
  theta : Inport  Port=6
  " m66" : Gain  Gain=m11
  Add : Sum  Inputs=+-
  Add1 : Sum  Inputs=--+-+
  DSC : Subsystem
  Divide : Product  Inputs=**
  Divide1 : Product  Inputs=**
  Divide2 : Product  Inputs=*/
  Fcn : Fcn  Expr=cos(u)
  Fcn1 : Fcn  Expr=u(1)
  Gain : Gain  Gain=ku
  Gain1 : Gain  Gain=m11
  Gain2 : Gain  Gain=m11
  Gain3 : Gain  Gain=m11
  Integrator : Integrator
  Scope1 : Scope
  Scope2 : Scope  NumInputPorts=2
  Subsystem1 : Subsystem
  Subsystem3 : Subsystem
  Sum1 : Sum  Inputs=+-
  Sum2 : Sum  Inputs=+-
  Sum3 : Sum  Inputs=+++--
  Sum4 : Sum
  To Workspace : ToWorkspace  VariableName=uncertainunn  SampleTime=-1
  To Workspace1 : ToWorkspace  VariableName=uncertainu  SampleTime=-1
  To Workspace2 : ToWorkspace  VariableName=nntaou  SampleTime=-1
  ka2 : Constant  Value=169
  m11 : Constant  Value=m11
  t_u : Outport
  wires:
  au/1 -> DSC/1(au)
  u/1 -> Add/1
  Gain/1 -> Gain2/1
  fu/1 -> Gain3/1
  DSC/1(b_u) -> Add/2
  Gain2/1 -> Add1/1
  [m11budot] -> Add1/3
  Add/1 -> [ue]
  [ue] -> Gain/1
  DSC/2(d_bu) -> Gain1/1
  Gain1/1 -> [m11budot]
  Subsystem3/1(W ̂u^T φu) -> [wufaiu]
  [V] -> Subsystem3/3(u)
  [ue] -> Subsystem3/1(ue)
  [wufaiu] -> Add1/2
  m11/1 -> Subsystem1/1(m11)
  [du] -> Subsystem1/3((D_u) ̂)
  [wufaiu] -> Subsystem1/5(W ̂u^T φu)
  [taou] -> Subsystem1/4(tao-u)
  [u] -> Subsystem1/2(u)
  Subsystem1/1(γzrZr) -> [rzuzu]
  Sum3/1 -> Integrator/1
  Integrator/1 -> Sum2/2
  " m66"/1 -> Sum2/1
  [ue] -> Sum3/4
  [du] -> Sum3/3
  [wufaiu] -> Sum3/2
  Sum2/1 -> [du]
  [rzuzu] -> Sum3/5
  [u] -> " m66"/1
  V/1 -> Fcn1/1, [V]
  Fcn1/1 -> [u]
  [rzuzu] -> Subsystem3/2(rzuzu)
  [du] -> Add1/4
  [du] -> Sum4/1
  [wufaiu] -> Sum4/2
  [taou] -> Sum3/1
  ka2/1 -> Sum1/1
  rous/1 -> [rous]
  [rous] -> Divide/2, Divide/1
  Divide/1 -> Sum1/2
  theta/1 -> [theta]
  [theta] -> Fcn/1
  Fcn/1 -> Divide1/1
  [rous] -> Divide1/2
  Divide1/1 -> Divide2/1
  Sum1/1 -> Divide2/2
  Divide2/1 -> Add1/5
  Gain3/1 -> To Workspace1/1, Scope2/1
  Sum4/1 -> To Workspace/1, Scope2/2
  Add1/1 -> Scope1/1, t_u/1, To Workspace2/1, [taou]

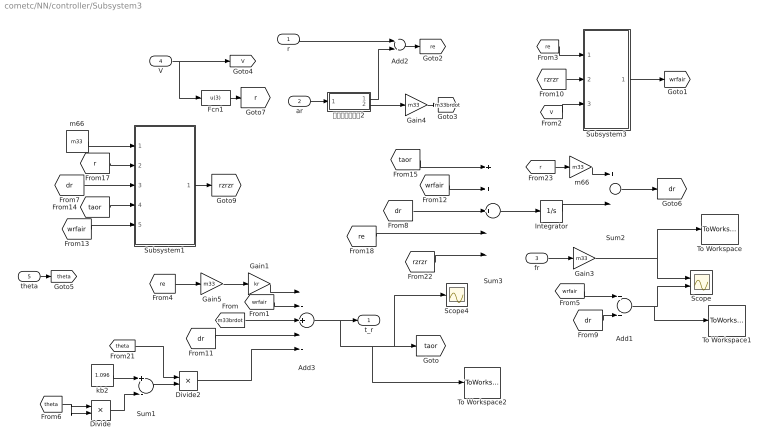
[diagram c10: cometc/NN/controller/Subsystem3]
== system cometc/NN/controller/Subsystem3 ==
  r : Inport
  ar : Inport  Port=2
  fr : Inport  Port=3
  V : Inport  Port=4
  theta : Inport  Port=5
  " m66" : Gain  Gain=m33
  Add1 : Sum
  Add2 : Sum  Inputs=+-
  Add3 : Sum  Inputs=--+--
  Divide : Product  Inputs=**
  Divide2 : Product  Inputs=*/
  Fcn1 : Fcn  Expr=u(3)
  Gain1 : Gain  Gain=kr
  Gain3 : Gain  Gain=m33
  Gain4 : Gain  Gain=m33
  Gain5 : Gain  Gain=m33
  Integrator : Integrator
  Scope : Scope  NumInputPorts=2
  Scope4 : Scope
  Subsystem1 : Subsystem
  Subsystem3 : Subsystem
  Sum1 : Sum  Inputs=+-
  Sum2 : Sum  Inputs=+-
  Sum3 : Sum  Inputs=+++--
  To Workspace : ToWorkspace  VariableName=uncertainr  SampleTime=-1
  To Workspace1 : ToWorkspace  VariableName=uncertainrnn  SampleTime=-1
  To Workspace2 : ToWorkspace  VariableName=nntaor  SampleTime=-1
  kb2 : Constant  Value=1.096
  m66 : Constant  Value=m33
  一阶低通滤波器2 : Subsystem
  t_r : Outport
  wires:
  ar/1 -> 一阶低通滤波器2/1(ar)
  r/1 -> Add2/1
  Add2/1 -> [re]
  Gain1/1 -> Add3/1
  fr/1 -> Gain3/1
  一阶低通滤波器2/1(ar1) -> Add2/2
  一阶低通滤波器2/2(d_ar) -> Gain4/1
  Gain5/1 -> Gain1/1
  Subsystem3/1(W ̂u^T φu) -> [wrfair]
  [V] -> Subsystem3/3(u)
  [re] -> Subsystem3/1(ue)
  V/1 -> Fcn1/1, [V]
  Gain4/1 -> [m33brdot]
  [m33brdot] -> Add3/3
  [wrfair] -> Add3/2
  [re] -> Gain5/1
  [wrfair] -> Add1/1
  m66/1 -> Subsystem1/1(m33)
  [dr] -> Subsystem1/3((D_r ) ̂)
  [wrfair] -> Subsystem1/5(W ̂r^T φr)
  [taor] -> Subsystem1/4(tao-r)
  [r] -> Subsystem1/2(r)
  Subsystem1/1(γzrZr) -> [rzrzr]
  Sum3/1 -> Integrator/1
  Integrator/1 -> Sum2/2
  " m66"/1 -> Sum2/1
  [re] -> Sum3/4
  [dr] -> Sum3/3
  [wrfair] -> Sum3/2
  [taor] -> Sum3/1
  Sum2/1 -> [dr]
  [rzrzr] -> Sum3/5
  [r] -> " m66"/1
  [rzrzr] -> Subsystem3/2(rzuzu)
  Fcn1/1 -> [r]
  [dr] -> Add1/2
  [dr] -> Add3/4
  kb2/1 -> Sum1/1
  [theta] -> Divide/2, Divide/1
  Divide/1 -> Sum1/2
  [theta] -> Divide2/1
  Sum1/1 -> Divide2/2
  Divide2/1 -> Add3/5
  theta/1 -> [theta]
  Gain3/1 -> Scope/1, To Workspace/1
  Add1/1 -> To Workspace1/1, Scope/2
  Add3/1 -> To Workspace2/1, Scope4/1, [taor], t_r/1

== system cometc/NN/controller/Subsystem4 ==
  x : Inport
  y : Inport  Port=2
  cosfai : Inport  Port=3
  sinfai : Inport  Port=4
  xdyd : Inport  Port=5
  deta1 : Inport  Port=6
  deta2 : Inport  Port=7
  v : Inport  Port=8
  Scope1 : Scope
  Scope2 : Scope
  Scope3 : Scope
  Subsystem : Subsystem
  纵向虚拟控制 : Subsystem
  alfau : Outport
  rou : Outport  Port=2
  theta : Outport  Port=3
  rous : Outport  Port=4
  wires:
  Subsystem/1(rou) -> rou/1, [rou]
  v/1 -> 纵向虚拟控制/3(v)
  deta2/1 -> 纵向虚拟控制/5(deta2)
  cosfai/1 -> Subsystem/3(cosp)
  纵向虚拟控制/1(au) -> Scope2/1, alfau/1
  deta1/1 -> 纵向虚拟控制/4(deta1)
  sinfai/1 -> Subsystem/4(sinp)
  x/1 -> Subsystem/1(x)
  xdyd/1 -> Subsystem/5(xdyd)
  y/1 -> Subsystem/2(y)
  [theta] -> 纵向虚拟控制/2(theta)
  Subsystem/2(theta) -> Scope3/1, theta/1, [theta]
  [rou] -> 纵向虚拟控制/1(rou)
  纵向虚拟控制/2(rous) -> Scope1/1, rous/1

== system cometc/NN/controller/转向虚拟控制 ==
  rou : Inport
  theta : Inport  Port=2
  u : Inport  Port=3
  v : Inport  Port=4
  deta1 : Inport  Port=5
  deta2 : Inport  Port=6
  Add : Sum
  Add1 : Sum  Inputs=--++
  Add2 : Sum  Inputs=+-
  Constant : Constant  Value=lam0
  Divide : Product  Inputs=*/
  Fcn2 : Fcn  Expr=sin(u)
  Fcn3 : Fcn  Expr=cos(u)
  Gain : Gain  Gain=ktheat
  Product{,1..3} (4 alike) : Product
  ar : Outport
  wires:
  theta/1 -> Fcn2/1, Add2/1, Fcn3/1
  Add1/1 -> Divide/1
  rou/1 -> Divide/2
  Product/1 -> Add1/4
  Product1/1 -> Add1/1
  Product3/1 -> Add1/2
  Product2/1 -> Add1/3
  u/1 -> Product1/2
  deta1/1 -> Product3/2
  v/1 -> Product2/2
  deta2/1 -> Product/2
  Fcn2/1 -> Product3/1, Product1/1
  Fcn3/1 -> Product/1, Product2/1
  Divide/1 -> Add/1
  Gain/1 -> Add/2
  Add/1 -> ar/1
  Add2/1 -> Gain/1
  Constant/1 -> Add2/2

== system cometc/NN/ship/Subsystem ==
  In1 : Inport
  MATLAB Function1 : MATLAB Function  TreatAsAtomicUnit=on
  Selector3 : Selector  InputPortWidth=3  IndexOptions=Index vector (dialog)  Indices=[3]  OutputSizes=1
  Out1 : Outport
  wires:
  Selector3/1 -> MATLAB Function1/1(psi)
  In1/1 -> Selector3/1
  MATLAB Function1/1(y) -> Out1/1

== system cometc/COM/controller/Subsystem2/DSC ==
  au : Inport
  Add : Sum  Inputs=-+
  Gain : Gain  Gain=1/T1
  Integrator : Integrator  InitialCondition=-5.37  UpperSaturationLimit=300  LowerSaturationLimit=-300
  b_u : Outport
  d_bu : Outport  Port=2
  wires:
  au/1 -> Add/2
  Gain/1 -> Integrator/1, d_bu/1
  Integrator/1 -> Add/1, b_u/1
  Add/1 -> Gain/1

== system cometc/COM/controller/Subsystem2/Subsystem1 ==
  m11 : Inport
  u : Inport  Port=2
  (D_u) ̂ : Inport  Port=3
  tao-u : Inport  Port=4
  W ̂u^T φu : Inport  Port=5
  Divide : Product  Inputs=*/
  Integrator2 : Integrator
  Sum6 : Sum  Inputs=++++
  Sum7 : Sum  Inputs=-+
  γzr : Gain  Gain=20
  ϕr : Gain  Gain=10
  γzrZr : Outport
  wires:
  ϕr/1 -> Sum6/2
  W ̂u^T φu/1 -> Sum6/3
  tao-u/1 -> Sum6/1
  (D_u) ̂/1 -> Sum6/4
  u/1 -> Sum7/2
  m11/1 -> Divide/2
  Sum7/1 -> ϕr/1, γzr/1
  Integrator2/1 -> Sum7/1
  γzr/1 -> γzrZr/1
  Sum6/1 -> Divide/1
  Divide/1 -> Integrator2/1

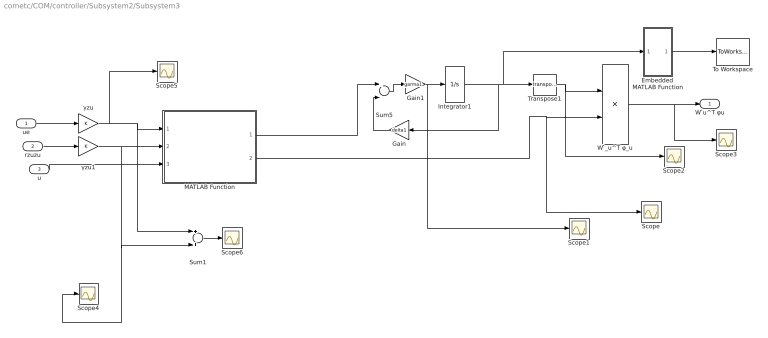
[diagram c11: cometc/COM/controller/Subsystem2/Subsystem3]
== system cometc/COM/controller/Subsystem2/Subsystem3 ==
  ue : Inport
  rzuzu : Inport  Port=2
  u : Inport  Port=3
  Embedded MATLAB Function : MATLAB Function  TreatAsAtomicUnit=on
  Gain : Gain  Gain=delta1
  Gain1 : Gain  Gain=garma1
  Integrator1 : Integrator
  MATLAB Function : MATLAB Function  TreatAsAtomicUnit=on
  Scope{,1..6} (7 alike) : Scope
  Sum1 : Sum
  Sum5 : Sum  Inputs=+-
  To Workspace : ToWorkspace  VariableName=comnormu  SampleTime=-1
  Transpose1 : Math  Operator=transpose
  W ̂_u^T φ_u : Product  Multiplication=Matrix(*)
  γzu : Gain
  γzu1 : Gain
  W ̂u^T φu : Outport
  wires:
  γzu1/1 -> MATLAB Function/2(rzuzu), Scope4/1, Sum1/2
  γzu/1 -> MATLAB Function/1(ue), Sum1/1, Scope5/1
  Sum1/1 -> Scope6/1
  W ̂_u^T φ_u/1 -> W ̂u^T φu/1, Scope3/1
  u/1 -> MATLAB Function/3(u)
  MATLAB Function/1(Ue_rzuZu_fai) -> Sum5/1
  Sum5/1 -> Gain1/1
  Transpose1/1 -> W ̂_u^T φ_u/1, Scope2/1
  MATLAB Function/2(fai) -> W ̂_u^T φ_u/2, Scope/1
  ue/1 -> γzu/1
  Gain/1 -> Sum5/2
  Gain1/1 -> Integrator1/1, Scope1/1
  rzuzu/1 -> γzu1/1
  Integrator1/1 -> Embedded MATLAB Function/1(u1), Transpose1/1, Gain/1
  Embedded MATLAB Function/1(y1) -> To Workspace/1

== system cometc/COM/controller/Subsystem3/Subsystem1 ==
  m33 : Inport
  r : Inport  Port=2
  (D_r ) ̂ : Inport  Port=3
  tao-r : Inport  Port=4
  W ̂r^T φr : Inport  Port=5
  Divide : Product  Inputs=*/
  Integrator2 : Integrator
  Sum6 : Sum  Inputs=++++
  Sum7 : Sum  Inputs=-+
  γzr : Gain  Gain=300
  ϕr : Gain  Gain=10
  γzrZr : Outport
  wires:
  ϕr/1 -> Sum6/2
  W ̂r^T φr/1 -> Sum6/3
  tao-r/1 -> Sum6/1
  (D_r ) ̂/1 -> Sum6/4
  r/1 -> Sum7/2
  m33/1 -> Divide/2
  Sum7/1 -> ϕr/1, γzr/1
  Integrator2/1 -> Sum7/1
  γzr/1 -> γzrZr/1
  Sum6/1 -> Divide/1
  Divide/1 -> Integrator2/1

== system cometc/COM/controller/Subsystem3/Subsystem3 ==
  ue : Inport
  rzuzu : Inport  Port=2
  u : Inport  Port=3
  Embedded MATLAB Function : MATLAB Function  TreatAsAtomicUnit=on
  Gain : Gain  Gain=delta2
  Gain1 : Gain  Gain=garma2
  Integrator1 : Integrator
  MATLAB Function : MATLAB Function  TreatAsAtomicUnit=on
  Scope{,1..6} (7 alike) : Scope
  Sum1 : Sum
  Sum5 : Sum  Inputs=+-
  To Workspace : ToWorkspace  VariableName=comnormr  SampleTime=-1
  Transpose1 : Math  Operator=transpose
  W ̂_u^T φ_u : Product  Multiplication=Matrix(*)
  γzu : Gain
  γzu1 : Gain
  W ̂u^T φu : Outport
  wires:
  γzu1/1 -> MATLAB Function/2(rzuzu), Scope4/1, Sum1/2
  γzu/1 -> MATLAB Function/1(ue), Sum1/1, Scope5/1
  Sum1/1 -> Scope6/1
  W ̂_u^T φ_u/1 -> W ̂u^T φu/1, Scope3/1
  u/1 -> MATLAB Function/3(u)
  MATLAB Function/1(Ue_rzuZu_fai) -> Sum5/1
  Sum5/1 -> Gain1/1
  Transpose1/1 -> W ̂_u^T φ_u/1, Scope2/1
  MATLAB Function/2(fai) -> W ̂_u^T φ_u/2, Scope/1
  ue/1 -> γzu/1
  Gain/1 -> Sum5/2
  Gain1/1 -> Integrator1/1, Scope1/1
  rzuzu/1 -> γzu1/1
  Integrator1/1 -> Embedded MATLAB Function/1(u1), Transpose1/1, Gain/1
  Embedded MATLAB Function/1(y1) -> To Workspace/1

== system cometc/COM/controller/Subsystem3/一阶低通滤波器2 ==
  ar : Inport
  Add : Sum  Inputs=-+
  Gain : Gain  Gain=1/T2
  Integrator : Integrator  InitialCondition=-0.32  UpperSaturationLimit=100  LowerSaturationLimit=-100
  ar1 : Outport
  d_ar : Outport  Port=2
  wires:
  ar/1 -> Add/2
  Gain/1 -> Integrator/1, d_ar/1
  Integrator/1 -> Add/1, ar1/1
  Add/1 -> Gain/1

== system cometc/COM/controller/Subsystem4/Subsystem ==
  x : Inport
  y : Inport  Port=2
  cosp : Inport  Port=3
  sinp : Inport  Port=4
  xdyd : Inport  Port=5
  Add : Sum  Inputs=+-
  Add1 : Sum  Inputs=+-
  Product{,1..3} (4 alike) : Product
  Scope{,1..3} (4 alike) : Scope
  Selector1 : Selector  InputPortWidth=2  IndexOptions=Index vector (dialog)  Indices=[2]  OutputSizes=1
  Selector4 : Selector  InputPortWidth=2  IndexOptions=Index vector (dialog)  Indices=[1]  OutputSizes=1
  xe : Sum
  ye : Sum  Inputs=-+
  距离和夹角 : MATLAB Function  TreatAsAtomicUnit=on
  rou : Outport
  theta : Outport  Port=2
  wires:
  xdyd/1 -> Selector4/1, Selector1/1
  距离和夹角/2(lam) -> theta/1
  距离和夹角/1(rou) -> rou/1
  Product/1 -> xe/1
  Selector1/1 -> Add1/2
  xe/1 -> 距离和夹角/1(xe), Scope/1
  ye/1 -> 距离和夹角/2(ye), Scope1/1
  Add1/1 -> Product3/1, Product2/1
  Product2/1 -> ye/2
  cosp/1 -> Product2/2, Product/2, Scope2/1
  y/1 -> Add1/1
  Selector4/1 -> Add/2
  Product3/1 -> xe/2
  Add/1 -> Product1/1, Product/1
  x/1 -> Add/1
  sinp/1 -> Product1/2, Product3/2, Scope3/1
  Product1/1 -> ye/1

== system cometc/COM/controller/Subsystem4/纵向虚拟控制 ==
  rou : Inport
  theta : Inport  Port=2
  v : Inport  Port=3
  deta1 : Inport  Port=4
  deta2 : Inport  Port=5
  Add : Sum  Inputs=----
  Add1 : Sum  Inputs=+-
  Constant : Constant  Value=rou0
  Divide : Product  Inputs=*/
  Fcn2 : Fcn  Expr=sin(u)
  Fcn3 : Fcn  Expr=cos(u)
  Gain : Gain  Gain=krou
  Product : Product
  Product1 : Product
  Product2 : Product
  Scope{,1..3} (4 alike) : Scope
  au : Outport
  rous : Outport  Port=2
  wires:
  Gain/1 -> Add/1, Scope1/1
  Divide/1 -> au/1
  Add/1 -> Divide/1
  Fcn3/1 -> Product1/2, Divide/2
  theta/1 -> Fcn2/1, Fcn3/1
  Product1/1 -> Add/3, Scope2/1
  Product2/1 -> Add/4, Scope3/1
  Constant/1 -> Add1/2
  Add1/1 -> Gain/1, rous/1
  Fcn2/1 -> Product/2, Product2/2
  deta1/1 -> Product1/1
  Product/1 -> Add/2, Scope/1
  deta2/1 -> Product2/1
  rou/1 -> Add1/1
  v/1 -> Product/1

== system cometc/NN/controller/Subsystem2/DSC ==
  au : Inport
  Add : Sum  Inputs=-+
  Gain : Gain  Gain=1/T1
  Integrator : Integrator  InitialCondition=-5.37  UpperSaturationLimit=300  LowerSaturationLimit=-300
  b_u : Outport
  d_bu : Outport  Port=2
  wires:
  Add/1 -> Gain/1
  Integrator/1 -> b_u/1, Add/1
  Gain/1 -> d_bu/1, Integrator/1
  au/1 -> Add/2

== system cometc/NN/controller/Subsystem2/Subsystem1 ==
  m11 : Inport
  u : Inport  Port=2
  (D_u) ̂ : Inport  Port=3
  tao-u : Inport  Port=4
  W ̂u^T φu : Inport  Port=5
  Divide : Product  Inputs=*/
  Integrator2 : Integrator
  Sum6 : Sum  Inputs=++++
  Sum7 : Sum  Inputs=-+
  γzr : Gain  Gain=0
  ϕr : Gain  Gain=10
  γzrZr : Outport
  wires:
  Divide/1 -> Integrator2/1
  Sum6/1 -> Divide/1
  γzr/1 -> γzrZr/1
  Integrator2/1 -> Sum7/1
  Sum7/1 -> γzr/1, ϕr/1
  m11/1 -> Divide/2
  u/1 -> Sum7/2
  (D_u) ̂/1 -> Sum6/4
  tao-u/1 -> Sum6/1
  W ̂u^T φu/1 -> Sum6/3
  ϕr/1 -> Sum6/2

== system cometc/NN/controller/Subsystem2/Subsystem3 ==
  ue : Inport
  rzuzu : Inport  Port=2
  u : Inport  Port=3
  Embedded MATLAB Function : MATLAB Function  TreatAsAtomicUnit=on
  Gain : Gain  Gain=delta1
  Gain1 : Gain  Gain=garma1
  Integrator1 : Integrator
  MATLAB Function : MATLAB Function  TreatAsAtomicUnit=on
  Scope{,1..6} (7 alike) : Scope
  Sum1 : Sum
  Sum5 : Sum  Inputs=+-
  To Workspace : ToWorkspace  VariableName=nnnormu  SampleTime=-1
  Transpose1 : Math  Operator=transpose
  W ̂_u^T φ_u : Product  Multiplication=Matrix(*)
  γzu : Gain
  γzu1 : Gain
  W ̂u^T φu : Outport
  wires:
  rzuzu/1 -> γzu1/1
  Gain1/1 -> Scope1/1, Integrator1/1
  Gain/1 -> Sum5/2
  ue/1 -> γzu/1
  MATLAB Function/2(fai) -> Scope/1, W ̂_u^T φ_u/2
  Transpose1/1 -> Scope2/1, W ̂_u^T φ_u/1
  Sum5/1 -> Gain1/1
  MATLAB Function/1(Ue_rzuZu_fai) -> Sum5/1
  u/1 -> MATLAB Function/3(u)
  W ̂_u^T φ_u/1 -> Scope3/1, W ̂u^T φu/1
  Sum1/1 -> Scope6/1
  γzu/1 -> Scope5/1, Sum1/1, MATLAB Function/1(ue)
  γzu1/1 -> Sum1/2, Scope4/1, MATLAB Function/2(rzuzu)
  Integrator1/1 -> Gain/1, Embedded MATLAB Function/1(u1), Transpose1/1
  Embedded MATLAB Function/1(y1) -> To Workspace/1

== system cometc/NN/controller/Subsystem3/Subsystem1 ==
  m33 : Inport
  r : Inport  Port=2
  (D_r ) ̂ : Inport  Port=3
  tao-r : Inport  Port=4
  W ̂r^T φr : Inport  Port=5
  Divide : Product  Inputs=*/
  Integrator2 : Integrator
  Sum6 : Sum  Inputs=++++
  Sum7 : Sum  Inputs=-+
  γzr : Gain  Gain=0
  ϕr : Gain  Gain=10
  γzrZr : Outport
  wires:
  Divide/1 -> Integrator2/1
  Sum6/1 -> Divide/1
  γzr/1 -> γzrZr/1
  Integrator2/1 -> Sum7/1
  Sum7/1 -> γzr/1, ϕr/1
  m33/1 -> Divide/2
  r/1 -> Sum7/2
  (D_r ) ̂/1 -> Sum6/4
  tao-r/1 -> Sum6/1
  W ̂r^T φr/1 -> Sum6/3
  ϕr/1 -> Sum6/2

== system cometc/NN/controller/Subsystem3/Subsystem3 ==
  ue : Inport
  rzuzu : Inport  Port=2
  u : Inport  Port=3
  Embedded MATLAB Function : MATLAB Function  TreatAsAtomicUnit=on
  Gain : Gain  Gain=delta2
  Gain1 : Gain  Gain=garma2
  Integrator1 : Integrator
  MATLAB Function : MATLAB Function  TreatAsAtomicUnit=on
  Scope{,1..6} (7 alike) : Scope
  Sum1 : Sum
  Sum5 : Sum  Inputs=+-
  To Workspace : ToWorkspace  VariableName=nnnormr  SampleTime=-1
  Transpose1 : Math  Operator=transpose
  W ̂_u^T φ_u : Product  Multiplication=Matrix(*)
  γzu : Gain
  γzu1 : Gain
  W ̂u^T φu : Outport
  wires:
  rzuzu/1 -> γzu1/1
  Gain1/1 -> Scope1/1, Integrator1/1
  Gain/1 -> Sum5/2
  ue/1 -> γzu/1
  MATLAB Function/2(fai) -> Scope/1, W ̂_u^T φ_u/2
  Transpose1/1 -> Scope2/1, W ̂_u^T φ_u/1
  Sum5/1 -> Gain1/1
  MATLAB Function/1(Ue_rzuZu_fai) -> Sum5/1
  u/1 -> MATLAB Function/3(u)
  W ̂_u^T φ_u/1 -> Scope3/1, W ̂u^T φu/1
  Sum1/1 -> Scope6/1
  γzu/1 -> Scope5/1, Sum1/1, MATLAB Function/1(ue)
  γzu1/1 -> Sum1/2, Scope4/1, MATLAB Function/2(rzuzu)
  Integrator1/1 -> Gain/1, Embedded MATLAB Function/1(u1), Transpose1/1
  Embedded MATLAB Function/1(y1) -> To Workspace/1

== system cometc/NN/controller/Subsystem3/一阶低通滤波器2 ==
  ar : Inport
  Add : Sum  Inputs=-+
  Gain : Gain  Gain=1/T2
  Integrator : Integrator  InitialCondition=-0.32  UpperSaturationLimit=100  LowerSaturationLimit=-100
  ar1 : Outport
  d_ar : Outport  Port=2
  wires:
  Add/1 -> Gain/1
  Integrator/1 -> ar1/1, Add/1
  Gain/1 -> d_ar/1, Integrator/1
  ar/1 -> Add/2

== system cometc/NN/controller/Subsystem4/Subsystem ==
  x : Inport
  y : Inport  Port=2
  cosp : Inport  Port=3
  sinp : Inport  Port=4
  xdyd : Inport  Port=5
  Add : Sum  Inputs=+-
  Add1 : Sum  Inputs=+-
  Product{,1..3} (4 alike) : Product
  Scope{,1..3} (4 alike) : Scope
  Selector1 : Selector  InputPortWidth=2  IndexOptions=Index vector (dialog)  Indices=[2]  OutputSizes=1
  Selector4 : Selector  InputPortWidth=2  IndexOptions=Index vector (dialog)  Indices=[1]  OutputSizes=1
  xe : Sum
  ye : Sum  Inputs=-+
  距离和夹角 : MATLAB Function  TreatAsAtomicUnit=on
  rou : Outport
  theta : Outport  Port=2
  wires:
  Product1/1 -> ye/1
  sinp/1 -> Scope3/1, Product3/2, Product1/2
  x/1 -> Add/1
  Add/1 -> Product/1, Product1/1
  Product3/1 -> xe/2
  Selector4/1 -> Add/2
  y/1 -> Add1/1
  cosp/1 -> Scope2/1, Product/2, Product2/2
  Product2/1 -> ye/2
  Add1/1 -> Product2/1, Product3/1
  ye/1 -> Scope1/1, 距离和夹角/2(ye)
  xe/1 -> Scope/1, 距离和夹角/1(xe)
  Selector1/1 -> Add1/2
  Product/1 -> xe/1
  距离和夹角/1(rou) -> rou/1
  距离和夹角/2(lam) -> theta/1
  xdyd/1 -> Selector1/1, Selector4/1

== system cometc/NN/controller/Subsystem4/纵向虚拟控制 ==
  rou : Inport
  theta : Inport  Port=2
  v : Inport  Port=3
  deta1 : Inport  Port=4
  deta2 : Inport  Port=5
  Add : Sum  Inputs=----
  Add1 : Sum  Inputs=+-
  Constant : Constant  Value=rou0
  Divide : Product  Inputs=*/
  Fcn2 : Fcn  Expr=sin(u)
  Fcn3 : Fcn  Expr=cos(u)
  Gain : Gain  Gain=krou
  Product : Product
  Product1 : Product
  Product2 : Product
  Scope{,1..3} (4 alike) : Scope
  au : Outport
  rous : Outport  Port=2
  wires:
  v/1 -> Product/1
  rou/1 -> Add1/1
  deta2/1 -> Product2/1
  Product/1 -> Scope/1, Add/2
  deta1/1 -> Product1/1
  Fcn2/1 -> Product2/2, Product/2
  Add1/1 -> rous/1, Gain/1
  Constant/1 -> Add1/2
  Product2/1 -> Scope3/1, Add/4
  Product1/1 -> Scope2/1, Add/3
  theta/1 -> Fcn3/1, Fcn2/1
  Fcn3/1 -> Divide/2, Product1/2
  Add/1 -> Divide/1
  Divide/1 -> au/1
  Gain/1 -> Scope1/1, Add/1

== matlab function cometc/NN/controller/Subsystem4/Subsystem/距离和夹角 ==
function [rou,lam] = fcn(xe,ye)
%#codegen
rou=sqrt(xe^2+ye^2);
lam=atan2(ye,xe);

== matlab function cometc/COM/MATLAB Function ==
function xdyd = fcn(t)
%#codegen
a=200*sin(0.02*t);
b=200*cos(0.02*t);
xdyd = [a;b];

== matlab function cometc/NN/controller/Subsystem3/Subsystem3/Embedded
MATLAB Function ==
function y1  = fcn(u1)
%#eml

y1=norm(u1);

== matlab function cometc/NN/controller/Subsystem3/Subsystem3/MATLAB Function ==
function [Ue_rzuZu_fai, fai] = Sfun(ue,rzuzu,u)

Z=[u']';


HideNode=20;
h=5;

r1=linspace(-2,20,HideNode);


Center=[r1];  
Sfun=ones(HideNode,1);


     for j = 1:1:HideNode
    
     Sfun(j)=exp(-((Z-Center(:,j))'*(Z-Center(:,j)))/h^2);
     end



Ue_rzuZu_fai = (ue+rzuzu) *Sfun;
fai = Sfun;

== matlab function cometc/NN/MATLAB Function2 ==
function [xd,yd,zd]= fcn(t)
%#codegen
% xd=200*sin(0.05*t);
% yd=200*cos(0.05*t);
xd=(15000*sin(0.3*t-pi/4)+15000*cos(0.2*t+pi/4)+15000*2);
yd=(1500*sin(0.2*t-pi/4)+15000*cos(0.3*t-pi/4)+1500*2)*1;
zd=(150000*cos(0.5*t-pi/4)+150000*sin(0.2*t+pi/4)-150000*3)*1;

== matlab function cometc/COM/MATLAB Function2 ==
function [xd,yd,zd]= fcn(t)
%#codegen
% xd=200*sin(0.05*t);
% yd=200*cos(0.05*t);
xd=(15000*sin(0.3*t-pi/4)+15000*cos(0.2*t+pi/4)+15000*2);
yd=(1500*sin(0.2*t-pi/4)+15000*cos(0.3*t-pi/4)+1500*2)*1;
zd=(150000*cos(0.5*t-pi/4)+150000*sin(0.2*t+pi/4)-150000*3)*1;

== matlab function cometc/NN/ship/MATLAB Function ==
function [dot,fu,fr] = fcn(u,v,r,tao_u,tao_r,tao_wu,tao_wv,tao_wr,m11,m22,m33,d11,d22,d33)
dot_u=(m22*v*r-d11*u+tao_u+tao_wu)/m11;
dot_v=(-m11*u*r-d22*v+tao_wv)/m22;
dot_r=((m11-m22)*u*v-d33*r+tao_r+tao_wr)/m33;
dot=[dot_u;dot_v;dot_r];
fu=(m22*v*r-d11*u+tao_wu)/m11;
fr=((m11-m22)*u*v-d33*r+tao_wr)/m33;

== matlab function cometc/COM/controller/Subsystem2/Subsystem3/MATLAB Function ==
function [Ue_rzuZu_fai, fai] = Sfun(ue,rzuzu,u)

Z=[u']';


HideNode=20;
h=5;

r1=linspace(-2,20,HideNode);


Center=[r1];  
Sfun=ones(HideNode,1);


     for j = 1:1:HideNode
    
     Sfun(j)=exp(-((Z-Center(:,j))'*(Z-Center(:,j)))/h^2);
     end



Ue_rzuZu_fai = (ue+rzuzu) *Sfun;
fai = Sfun;

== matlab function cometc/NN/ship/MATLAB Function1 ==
function [dot,fu,fr] = fcn(u,v,r,d11,d22,d33,m11,m22,m33)
dot_u=(-0.24*d11*abs(u)*u)/m11;
dot_v=(-0.24*d22*abs(v)*v)/m22;
dot_r=(-0.24*d33*abs(r)*r)/m33;
dot=[dot_u;dot_v;dot_r];
fu=(-0.24*d11*abs(u)*u)/m11;
fr=(-0.24*d33*abs(r)*r)/m33;

== matlab function cometc/COM/controller/Subsystem2/Subsystem3/Embedded
MATLAB Function ==
function y1  = fcn(u1)
%#eml

y1=norm(u1);

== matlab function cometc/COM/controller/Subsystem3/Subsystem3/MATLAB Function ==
function [Ue_rzuZu_fai, fai] = Sfun(ue,rzuzu,u)

Z=[u']';


HideNode=20;
h=5;

r1=linspace(-2,20,HideNode);


Center=[r1];  
Sfun=ones(HideNode,1);


     for j = 1:1:HideNode
    
     Sfun(j)=exp(-((Z-Center(:,j))'*(Z-Center(:,j)))/h^2);
     end



Ue_rzuZu_fai = (ue+rzuzu) *Sfun;
fai = Sfun;

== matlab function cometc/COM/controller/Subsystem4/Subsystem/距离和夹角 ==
function [rou,lam] = fcn(xe,ye)
%#codegen
rou=sqrt(xe^2+ye^2);
lam=atan2(ye,xe);

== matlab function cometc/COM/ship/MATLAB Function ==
function [dot,fu,fr] = fcn(u,v,r,tao_u,tao_r,tao_wu,tao_wv,tao_wr,m11,m22,m33,d11,d22,d33)
dot_u=(m22*v*r-d11*u+tao_u+tao_wu)/m11;
dot_v=(-m11*u*r-d22*v+tao_wv)/m22;
dot_r=((m11-m22)*u*v-d33*r+tao_r+tao_wr)/m33;
dot=[dot_u;dot_v;dot_r];
fu=(m22*v*r-d11*u+tao_wu)/m11;
fr=((m11-m22)*u*v-d33*r+tao_wr)/m33;

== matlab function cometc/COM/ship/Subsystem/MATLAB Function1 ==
function y = fcn(psi)
%#codegen

y =[cos(psi) -sin(psi) 0;sin(psi) cos(psi) 0;0 0 1];

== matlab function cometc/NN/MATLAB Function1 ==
function xdyd = fcn(t)
%#codegen
a=200*sin(0.02*t);
b=200*cos(0.02*t);
xdyd = [a;b];

== matlab function cometc/COM/controller/Subsystem3/Subsystem3/Embedded
MATLAB Function ==
function y1  = fcn(u1)
%#eml

y1=norm(u1);

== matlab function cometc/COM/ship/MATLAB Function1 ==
function [dot,fu,fr] = fcn(u,v,r,d11,d22,d33,m11,m22,m33)
dot_u=(-0.24*d11*abs(u)*u)/m11;
dot_v=(-0.24*d22*abs(v)*v)/m22;
dot_r=(-0.24*d33*abs(r)*r)/m33;
dot=[dot_u;dot_v;dot_r];
fu=(-0.24*d11*abs(u)*u)/m11;
fr=(-0.24*d33*abs(r)*r)/m33;

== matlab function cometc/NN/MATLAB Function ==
function xdyd = fcn(t)
%#codegen
a=200*sin(0.02*t);
b=200*cos(0.02*t);
xdyd = [a;b];

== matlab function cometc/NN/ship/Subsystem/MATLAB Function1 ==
function y = fcn(psi)
%#codegen

y =[cos(psi) -sin(psi) 0;sin(psi) cos(psi) 0;0 0 1];

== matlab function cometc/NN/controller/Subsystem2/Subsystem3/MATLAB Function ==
function [Ue_rzuZu_fai, fai] = Sfun(ue,rzuzu,u)

Z=[u']';


HideNode=20;
h=5;

r1=linspace(-2,20,HideNode);


Center=[r1];  
Sfun=ones(HideNode,1);


     for j = 1:1:HideNode
    
     Sfun(j)=exp(-((Z-Center(:,j))'*(Z-Center(:,j)))/h^2);
     end



Ue_rzuZu_fai = (ue+rzuzu) *Sfun;
fai = Sfun;

== matlab function cometc/NN/controller/Subsystem2/Subsystem3/Embedded
MATLAB Function ==
function y1  = fcn(u1)
%#eml

y1=norm(u1);
